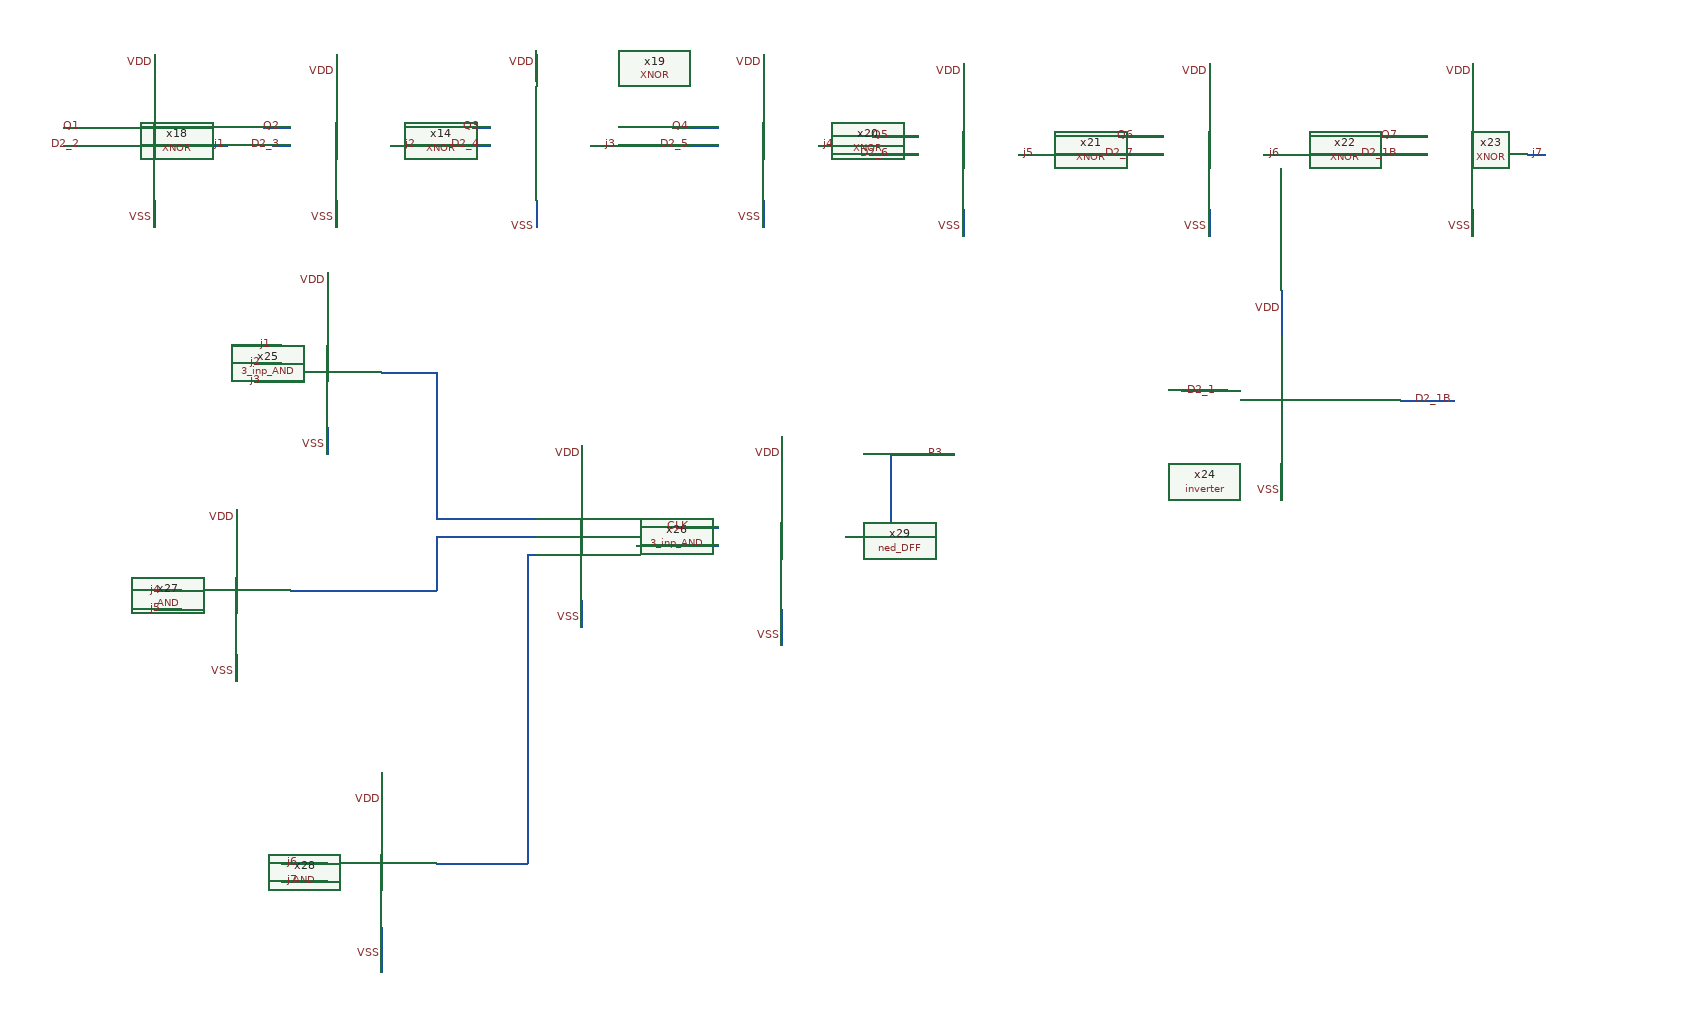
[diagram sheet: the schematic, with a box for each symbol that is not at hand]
v {xschem version=3.1.0 file_version=1.2
}
G {}
K {}
V {}
S {}
E {}
N -2650 -1120 -2600 -1120 {
lab=Q1}
N -2650 -1100 -2600 -1100 {
lab=D2_2}
N -2430 -1120 -2400 -1120 {
lab=Q2}
N -2420 -1100 -2400 -1100 {
lab=D2_3}
N -2200 -1120 -2180 -1120 {
lab=Q3}
N -2200 -1100 -2180 -1100 {
lab=D2_4}
N -2290 -1100 -2260 -1100 {
lab=j2}
N -2550 -1200 -2550 -1170 {
lab=VDD}
N -2550 -1040 -2550 -1010 {
lab=VSS}
N -2350 -1200 -2350 -1170 {
lab=VDD}
N -2350 -1040 -2350 -1010 {
lab=VSS}
N -2130 -1200 -2130 -1170 {
lab=VDD}
N -2130 -1040 -2130 -1010 {
lab=VSS}
N -2070 -1100 -2040 -1100 {
lab=j3}
N -2490 -1100 -2470 -1100 {
lab=j1}
N -1980 -1120 -1930 -1120 {
lab=Q4}
N -1980 -1100 -1930 -1100 {
lab=D2_5}
N -1880 -1200 -1880 -1170 {
lab=VDD}
N -1880 -1040 -1880 -1010 {
lab=VSS}
N -1820 -1100 -1800 -1100 {
lab=j4}
N -1760 -1110 -1710 -1110 {
lab=Q5}
N -1760 -1090 -1710 -1090 {
lab=D2_6}
N -1660 -1190 -1660 -1160 {
lab=VDD}
N -1660 -1030 -1660 -1000 {
lab=VSS}
N -1600 -1090 -1580 -1090 {
lab=j5}
N -1490 -1110 -1440 -1110 {
lab=Q6}
N -1490 -1090 -1440 -1090 {
lab=D2_7}
N -1390 -1190 -1390 -1160 {
lab=VDD}
N -1390 -1030 -1390 -1000 {
lab=VSS}
N -1330 -1090 -1310 -1090 {
lab=j6}
N -1200 -1110 -1150 -1110 {
lab=Q7}
N -1200 -1090 -1150 -1090 {
lab=D2_1B}
N -1100 -1190 -1100 -1160 {
lab=VDD}
N -1100 -1030 -1100 -1000 {
lab=VSS}
N -1040 -1090 -1020 -1090 {
lab=j7}
N -1180 -820 -1120 -820 {
lab=D2_1B}
N -1420 -830 -1370 -830 {
lab=D2_1}
N -1310 -940 -1310 -890 {
lab=VDD}
N -1310 -750 -1310 -710 {
lab=VSS}
N -2440 -880 -2410 -880 {
lab=j1}
N -2440 -860 -2410 -860 {
lab=j2}
N -2440 -840 -2410 -840 {
lab=j3}
N -2360 -960 -2360 -930 {
lab=VDD}
N -1740 -760 -1670 -760 {
lab=P3}
N -2360 -790 -2360 -760 {
lab=VSS}
N -2550 -610 -2520 -610 {
lab=j4}
N -2550 -590 -2520 -590 {
lab=j5}
N -2460 -700 -2460 -670 {
lab=VDD}
N -2460 -540 -2460 -510 {
lab=VSS}
N -2300 -410 -2300 -370 {
lab=VDD}
N -2300 -240 -2300 -190 {
lab=VSS}
N -2410 -310 -2360 -310 {
lab=j6}
N -2410 -290 -2360 -290 {
lab=j7}
N -2160 -690 -2130 -690 {
lab=#net6}
N -2160 -670 -2130 -670 {
lab=#net7}
N -2080 -770 -2080 -740 {
lab=VDD}
N -2080 -600 -2080 -570 {
lab=VSS}
N -2300 -850 -2240 -850 {
lab=#net6}
N -2240 -850 -2240 -690 {
lab=#net6}
N -2240 -690 -2160 -690 {
lab=#net6}
N -2310 -610 -2240 -610 {
lab=#net7}
N -2240 -670 -2240 -610 {
lab=#net7}
N -2240 -670 -2160 -670 {
lab=#net7}
N -2140 -650 -2130 -650 {
lab=#net8}
N -2020 -660 -1960 -660 {
lab=#net9}
N -2140 -650 -2140 -310 {
lab=#net8}
N -2400 -610 -2310 -610 {
lab=#net7}
N -2240 -310 -2140 -310 {
lab=#net8}
N -1740 -740 -1740 -680 {
lab=P3}
N -1860 -780 -1860 -740 {
lab=VDD}
N -1860 -590 -1860 -550 {
lab=VSS}
N -1970 -680 -1930 -680 {
lab=CLK}
N -1790 -670 -1750 -670 {
lab=P3}
N -1960 -660 -1930 -660 {
lab=#net9}
N -1750 -670 -1740 -670 {
lab=P3}
N -1740 -680 -1740 -670 {
lab=P3}
N -1740 -760 -1740 -740 {
lab=P3}
C {XNOR.sym} -2250 -1100 0 0 {name=x14}
C {XNOR.sym} -2450 -1100 0 0 {name=x18}
C {XNOR.sym} -2030 -1100 0 0 {name=x19}
C {devices/lab_wire.sym} -2550 -1190 0 0 {name=p68 sig_type=std_logic lab=VDD}
C {devices/lab_wire.sym} -2350 -1180 0 0 {name=p73 sig_type=std_logic lab=VDD}
C {devices/lab_wire.sym} -2130 -1190 0 0 {name=p74 sig_type=std_logic lab=VDD}
C {devices/lab_wire.sym} -2550 -1020 0 0 {name=p78 sig_type=std_logic lab=VSS}
C {devices/lab_wire.sym} -2350 -1020 0 0 {name=p79 sig_type=std_logic lab=VSS}
C {devices/lab_wire.sym} -2630 -1120 0 0 {name=p82 sig_type=std_logic lab=Q1}
C {devices/lab_wire.sym} -2410 -1120 0 0 {name=p89 sig_type=std_logic lab=Q2}
C {devices/lab_wire.sym} -2190 -1120 0 0 {name=p90 sig_type=std_logic lab=Q3}
C {devices/lab_wire.sym} -2190 -1100 0 0 {name=p91 sig_type=std_logic lab=D2_4}
C {devices/lab_wire.sym} -2410 -1100 0 0 {name=p92 sig_type=std_logic lab=D2_3}
C {devices/lab_wire.sym} -2630 -1100 0 0 {name=p93 sig_type=std_logic lab=D2_2}
C {devices/lab_wire.sym} -2470 -1100 0 0 {name=p96 sig_type=std_logic lab=j1}
C {XNOR.sym} -1780 -1100 0 0 {name=x20}
C {devices/lab_wire.sym} -1880 -1190 0 0 {name=p99 sig_type=std_logic lab=VDD}
C {devices/lab_wire.sym} -1880 -1020 0 0 {name=p100 sig_type=std_logic lab=VSS}
C {devices/lab_wire.sym} -1960 -1120 0 0 {name=p101 sig_type=std_logic lab=Q4}
C {devices/lab_wire.sym} -1960 -1100 0 0 {name=p102 sig_type=std_logic lab=D2_5}
C {XNOR.sym} -1560 -1090 0 0 {name=x21}
C {devices/lab_wire.sym} -1660 -1180 0 0 {name=p104 sig_type=std_logic lab=VDD}
C {devices/lab_wire.sym} -1660 -1010 0 0 {name=p105 sig_type=std_logic lab=VSS}
C {devices/lab_wire.sym} -1740 -1110 0 0 {name=p106 sig_type=std_logic lab=Q5}
C {devices/lab_wire.sym} -1740 -1090 0 0 {name=p107 sig_type=std_logic lab=D2_6}
C {XNOR.sym} -1290 -1090 0 0 {name=x22}
C {devices/lab_wire.sym} -1390 -1180 0 0 {name=p109 sig_type=std_logic lab=VDD}
C {devices/lab_wire.sym} -1390 -1010 0 0 {name=p110 sig_type=std_logic lab=VSS}
C {devices/lab_wire.sym} -1470 -1110 0 0 {name=p111 sig_type=std_logic lab=Q6}
C {devices/lab_wire.sym} -1470 -1090 0 0 {name=p112 sig_type=std_logic lab=D2_7}
C {XNOR.sym} -1000 -1090 0 0 {name=x23}
C {devices/lab_wire.sym} -1100 -1180 0 0 {name=p114 sig_type=std_logic lab=VDD}
C {devices/lab_wire.sym} -1100 -1010 0 0 {name=p115 sig_type=std_logic lab=VSS}
C {devices/lab_wire.sym} -1180 -1110 0 0 {name=p116 sig_type=std_logic lab=Q7}
C {devices/lab_wire.sym} -1180 -1090 0 0 {name=p118 sig_type=std_logic lab=D2_1B}
C {inverter.sym} -1220 -810 0 0 {name=x24}
C {devices/lab_wire.sym} -1310 -920 0 0 {name=p119 sig_type=std_logic lab=VDD}
C {devices/lab_wire.sym} -1310 -720 0 0 {name=p120 sig_type=std_logic lab=VSS}
C {devices/lab_wire.sym} -1380 -830 0 0 {name=p121 sig_type=std_logic lab=D2_1}
C {devices/lab_wire.sym} -1120 -820 0 0 {name=p122 sig_type=std_logic lab=D2_1B}
C {devices/lab_wire.sym} -2260 -1100 0 0 {name=p97 sig_type=std_logic lab=j2}
C {devices/lab_wire.sym} -2040 -1100 0 0 {name=p98 sig_type=std_logic lab=j3}
C {devices/lab_wire.sym} -1800 -1100 0 0 {name=p103 sig_type=std_logic lab=j4}
C {devices/lab_wire.sym} -1580 -1090 0 0 {name=p108 sig_type=std_logic lab=j5}
C {devices/lab_wire.sym} -1310 -1090 0 0 {name=p113 sig_type=std_logic lab=j6}
C {devices/lab_wire.sym} -1020 -1090 0 0 {name=p117 sig_type=std_logic lab=j7}
C {devices/lab_wire.sym} -2360 -770 0 0 {name=p123 sig_type=std_logic lab=VSS}
C {3_inp_AND.sym} -2260 -860 0 0 {name=x25}
C {devices/lab_wire.sym} -2360 -950 0 0 {name=p124 sig_type=std_logic lab=VDD}
C {devices/lab_wire.sym} -2460 -520 0 0 {name=p127 sig_type=std_logic lab=VSS}
C {devices/lab_wire.sym} -2460 -690 0 0 {name=p128 sig_type=std_logic lab=VDD}
C {devices/lab_wire.sym} -2300 -380 0 0 {name=p132 sig_type=std_logic lab=VDD}
C {devices/lab_wire.sym} -2300 -210 0 0 {name=p133 sig_type=std_logic lab=VSS}
C {devices/lab_wire.sym} -2080 -580 0 0 {name=p134 sig_type=std_logic lab=VSS}
C {3_inp_AND.sym} -1980 -670 0 0 {name=x26}
C {devices/lab_wire.sym} -2080 -760 0 0 {name=p135 sig_type=std_logic lab=VDD}
C {AND.sym} -2370 -590 0 0 {name=x27}
C {AND.sym} -2210 -290 0 0 {name=x28}
C {devices/lab_wire.sym} -1860 -760 0 0 {name=p139 sig_type=std_logic lab=VDD}
C {devices/lab_wire.sym} -1860 -560 0 0 {name=p140 sig_type=std_logic lab=VSS}
C {devices/lab_wire.sym} -1680 -760 0 0 {name=p141 sig_type=std_logic lab=P3}
C {devices/lab_wire.sym} -1960 -680 0 0 {name=p142 sig_type=std_logic lab=CLK}
C {devices/lab_wire.sym} -2420 -880 0 0 {name=p125 sig_type=std_logic lab=j1}
C {devices/lab_wire.sym} -2430 -860 0 0 {name=p129 sig_type=std_logic lab=j2}
C {devices/lab_wire.sym} -2430 -840 0 0 {name=p130 sig_type=std_logic lab=j3}
C {devices/lab_wire.sym} -2540 -610 0 0 {name=p131 sig_type=std_logic lab=j4}
C {devices/lab_wire.sym} -2540 -590 0 0 {name=p136 sig_type=std_logic lab=j5}
C {devices/lab_wire.sym} -2390 -310 0 0 {name=p137 sig_type=std_logic lab=j6}
C {devices/lab_wire.sym} -2390 -290 0 0 {name=p138 sig_type=std_logic lab=j7}
C {ned_DFF.sym} -1780 -660 0 0 {name=x29}
C {devices/lab_wire.sym} -2130 -1010 0 0 {name=p148 sig_type=std_logic lab=VSS}
